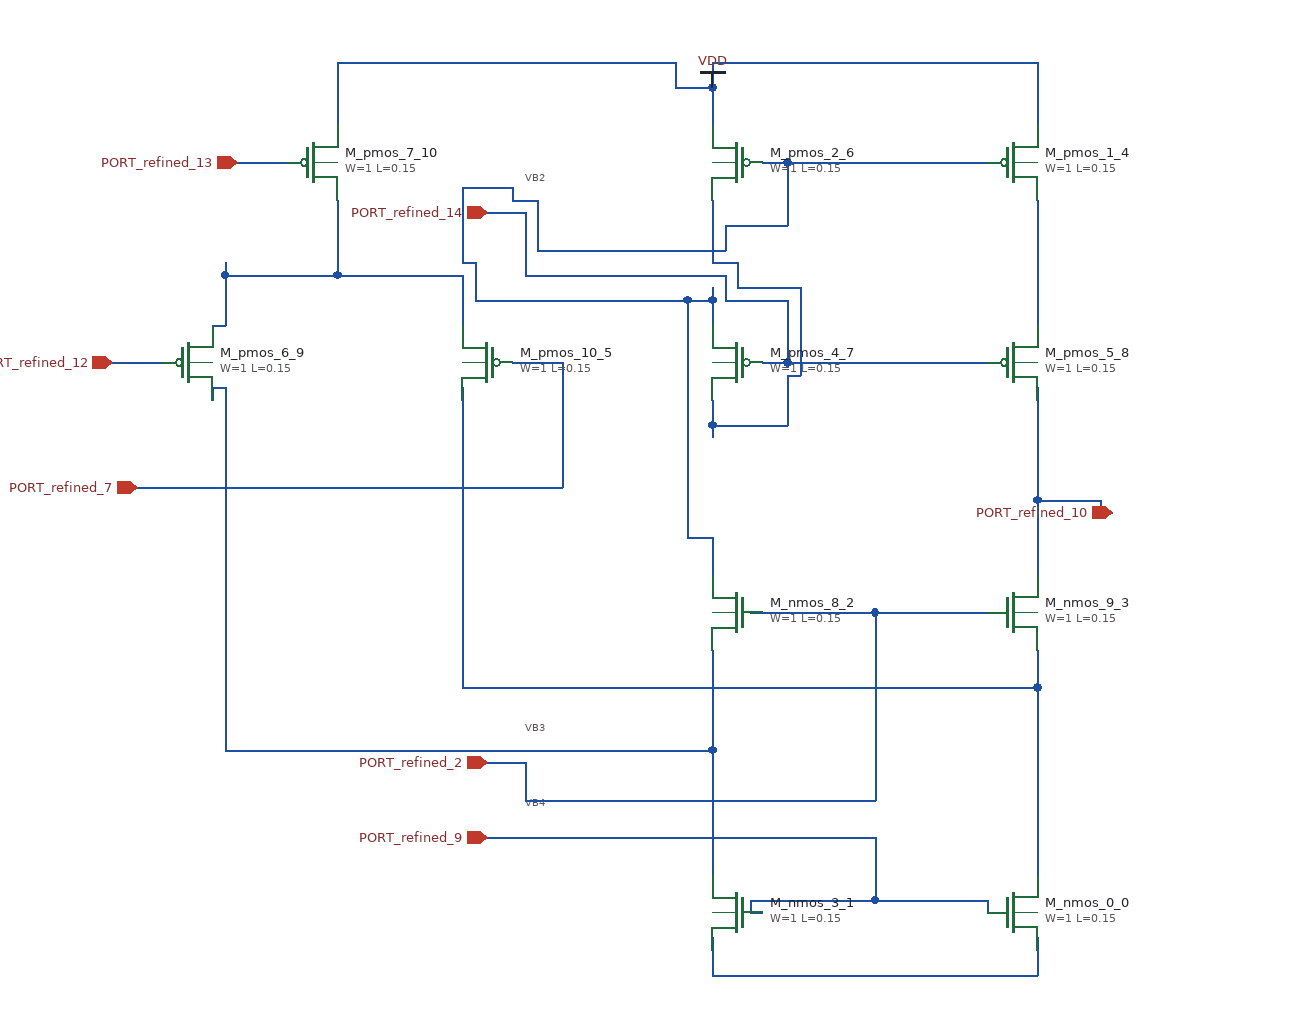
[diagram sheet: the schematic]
v {xschem version=3.4.8 file_version=1.2}
G {}
K {}
V {}
S {}
E {}
C {sky130_fd_pr/nfet3_01v8.sym} 780 720 0 0 {name="M_nmos_0_0"
W=1
L=0.15
body=GND
nf=1
mult=1
ad="expr('int((@nf + 1)/2) * @W / @nf * 0.29')"
pd="expr('2*int((@nf + 1)/2) * (@W / @nf + 0.29)')"
as="expr('int((@nf + 2)/2) * @W / @nf * 0.29')"
ps="expr('2*int((@nf + 2)/2) * (@W / @nf + 0.29)')"
nrd="expr('0.29 / @W ')" nrs="expr('0.29 / @W ')"
sa=0 sb=0 sd=0
model=nfet_01v8
spiceprefix=X
}
C {sky130_fd_pr/nfet3_01v8.sym} 560 720 0 1 {name="M_nmos_3_1"
W=1
L=0.15
body=GND
nf=1
mult=1
ad="expr('int((@nf + 1)/2) * @W / @nf * 0.29')"
pd="expr('2*int((@nf + 1)/2) * (@W / @nf + 0.29)')"
as="expr('int((@nf + 2)/2) * @W / @nf * 0.29')"
ps="expr('2*int((@nf + 2)/2) * (@W / @nf + 0.29)')"
nrd="expr('0.29 / @W ')" nrs="expr('0.29 / @W ')"
sa=0 sb=0 sd=0
model=nfet_01v8
spiceprefix=X
}
C {sky130_fd_pr/nfet3_01v8.sym} 560 480 0 1 {name="M_nmos_8_2"
W=1
L=0.15
body=GND
nf=1
mult=1
ad="expr('int((@nf + 1)/2) * @W / @nf * 0.29')"
pd="expr('2*int((@nf + 1)/2) * (@W / @nf + 0.29)')"
as="expr('int((@nf + 2)/2) * @W / @nf * 0.29')"
ps="expr('2*int((@nf + 2)/2) * (@W / @nf + 0.29)')"
nrd="expr('0.29 / @W ')" nrs="expr('0.29 / @W ')"
sa=0 sb=0 sd=0
model=nfet_01v8
spiceprefix=X
}
C {sky130_fd_pr/nfet3_01v8.sym} 780 480 0 0 {name="M_nmos_9_3"
W=1
L=0.15
body=GND
nf=1
mult=1
ad="expr('int((@nf + 1)/2) * @W / @nf * 0.29')"
pd="expr('2*int((@nf + 1)/2) * (@W / @nf + 0.29)')"
as="expr('int((@nf + 2)/2) * @W / @nf * 0.29')"
ps="expr('2*int((@nf + 2)/2) * (@W / @nf + 0.29)')"
nrd="expr('0.29 / @W ')" nrs="expr('0.29 / @W ')"
sa=0 sb=0 sd=0
model=nfet_01v8
spiceprefix=X
}
C {sky130_fd_pr/pfet3_01v8.sym} 780 120 0 0 {name="M_pmos_1_4"
W=1
L=0.15
body=VDD
nf=1
mult=1
ad="expr('int((@nf + 1)/2) * @W / @nf * 0.29')"
pd="expr('2*int((@nf + 1)/2) * (@W / @nf + 0.29)')"
as="expr('int((@nf + 2)/2) * @W / @nf * 0.29')"
ps="expr('2*int((@nf + 2)/2) * (@W / @nf + 0.29)')"
nrd="expr('0.29 / @W ')" nrs="expr('0.29 / @W ')"
sa=0 sb=0 sd=0
model=pfet_01v8
spiceprefix=X
}
C {sky130_fd_pr/pfet3_01v8.sym} 360 280 0 1 {name="M_pmos_10_5"
W=1
L=0.15
body=VDD
nf=1
mult=1
ad="expr('int((@nf + 1)/2) * @W / @nf * 0.29')"
pd="expr('2*int((@nf + 1)/2) * (@W / @nf + 0.29)')"
as="expr('int((@nf + 2)/2) * @W / @nf * 0.29')"
ps="expr('2*int((@nf + 2)/2) * (@W / @nf + 0.29)')"
nrd="expr('0.29 / @W ')" nrs="expr('0.29 / @W ')"
sa=0 sb=0 sd=0
model=pfet_01v8
spiceprefix=X
}
C {sky130_fd_pr/pfet3_01v8.sym} 560 120 0 1 {name="M_pmos_2_6"
W=1
L=0.15
body=VDD
nf=1
mult=1
ad="expr('int((@nf + 1)/2) * @W / @nf * 0.29')"
pd="expr('2*int((@nf + 1)/2) * (@W / @nf + 0.29)')"
as="expr('int((@nf + 2)/2) * @W / @nf * 0.29')"
ps="expr('2*int((@nf + 2)/2) * (@W / @nf + 0.29)')"
nrd="expr('0.29 / @W ')" nrs="expr('0.29 / @W ')"
sa=0 sb=0 sd=0
model=pfet_01v8
spiceprefix=X
}
C {sky130_fd_pr/pfet3_01v8.sym} 560 280 2 0 {name="M_pmos_4_7"
W=1
L=0.15
body=VDD
nf=1
mult=1
ad="expr('int((@nf + 1)/2) * @W / @nf * 0.29')"
pd="expr('2*int((@nf + 1)/2) * (@W / @nf + 0.29)')"
as="expr('int((@nf + 2)/2) * @W / @nf * 0.29')"
ps="expr('2*int((@nf + 2)/2) * (@W / @nf + 0.29)')"
nrd="expr('0.29 / @W ')" nrs="expr('0.29 / @W ')"
sa=0 sb=0 sd=0
model=pfet_01v8
spiceprefix=X
}
C {sky130_fd_pr/pfet3_01v8.sym} 780 280 0 0 {name="M_pmos_5_8"
W=1
L=0.15
body=VDD
nf=1
mult=1
ad="expr('int((@nf + 1)/2) * @W / @nf * 0.29')"
pd="expr('2*int((@nf + 1)/2) * (@W / @nf + 0.29)')"
as="expr('int((@nf + 2)/2) * @W / @nf * 0.29')"
ps="expr('2*int((@nf + 2)/2) * (@W / @nf + 0.29)')"
nrd="expr('0.29 / @W ')" nrs="expr('0.29 / @W ')"
sa=0 sb=0 sd=0
model=pfet_01v8
spiceprefix=X
}
C {sky130_fd_pr/pfet3_01v8.sym} 120 280 0 0 {name="M_pmos_6_9"
W=1
L=0.15
body=VDD
nf=1
mult=1
ad="expr('int((@nf + 1)/2) * @W / @nf * 0.29')"
pd="expr('2*int((@nf + 1)/2) * (@W / @nf + 0.29)')"
as="expr('int((@nf + 2)/2) * @W / @nf * 0.29')"
ps="expr('2*int((@nf + 2)/2) * (@W / @nf + 0.29)')"
nrd="expr('0.29 / @W ')" nrs="expr('0.29 / @W ')"
sa=0 sb=0 sd=0
model=pfet_01v8
spiceprefix=X
}
C {sky130_fd_pr/pfet3_01v8.sym} 220 120 0 0 {name="M_pmos_7_10"
W=1
L=0.15
body=VDD
nf=1
mult=1
ad="expr('int((@nf + 1)/2) * @W / @nf * 0.29')"
pd="expr('2*int((@nf + 1)/2) * (@W / @nf + 0.29)')"
as="expr('int((@nf + 2)/2) * @W / @nf * 0.29')"
ps="expr('2*int((@nf + 2)/2) * (@W / @nf + 0.29)')"
nrd="expr('0.29 / @W ')" nrs="expr('0.29 / @W ')"
sa=0 sb=0 sd=0
model=pfet_01v8
spiceprefix=X
}
C {devices/ipin.sym} 60 280 0 0 {name="p_port_12_11" lab="PORT_refined_12"}
C {devices/ipin.sym} 860 400 0 0 {name="p_port_13_12" lab="PORT_refined_10"}
C {devices/ipin.sym} 160 120 0 0 {name="p_port_14_13" lab="PORT_refined_13"}
C {devices/ipin.sym} 80 380 0 0 {name="p_port_15_14" lab="PORT_refined_7"}
C {devices/ipin.sym} 360 160 0 0 {name="p_port_20_15" lab="PORT_refined_14"}
T {VB2} 390 120 0 0 0.25 0.25 {}
C {devices/ipin.sym} 360 600 0 0 {name="p_port_21_16" lab="PORT_refined_2"}
T {VB3} 390 560 0 0 0.25 0.25 {}
C {devices/ipin.sym} 360 660 0 0 {name="p_port_22_17" lab="PORT_refined_9"}
T {VB4} 390 620 0 0 0.25 0.25 {}
C {devices/vdd.sym} 540 60 0 0 {name="l_vdd_11_18" lab="VDD"}
N 340 540 800 540 {}
N 340 540 340 310 {}
N 340 310 340 300 {}
N 800 690 800 540 {}
N 800 540 800 510 {}
N 540 770 800 770 {}
N 540 770 540 750 {}
N 540 750 540 740 {}
N 800 770 800 750 {}
N 800 750 800 740 {}
N 850 400 860 400 {}
N 800 390 850 390 {}
N 800 460 800 450 {}
N 800 450 800 390 {}
N 800 390 800 310 {}
N 800 310 800 300 {}
N 850 400 850 390 {}
N 150 590 540 590 {}
N 140 300 150 300 {}
N 140 310 140 300 {}
N 150 590 150 300 {}
N 540 690 540 590 {}
N 540 590 540 510 {}
N 60 280 100 280 {}
N 100 280 110 280 {}
N 160 120 200 120 {}
N 580 280 600 280 {}
N 600 280 760 280 {}
N 550 230 600 230 {}
N 390 210 550 210 {}
N 360 160 390 160 {}
N 390 210 390 160 {}
N 550 230 550 210 {}
N 600 280 600 230 {}
N 390 630 670 630 {}
N 360 600 390 600 {}
N 570 480 580 480 {}
N 580 480 670 480 {}
N 670 480 760 480 {}
N 390 630 390 600 {}
N 670 630 670 480 {}
N 510 60 540 60 {}
N 240 40 510 40 {}
N 540 40 800 40 {}
N 240 90 240 40 {}
N 510 60 510 40 {}
N 540 90 540 60 {}
N 540 60 540 40 {}
N 800 90 800 40 {}
N 800 250 800 150 {}
N 520 420 540 420 {}
N 350 230 520 230 {}
N 520 230 540 230 {}
N 340 200 350 200 {}
N 400 190 550 190 {}
N 550 170 600 170 {}
N 380 150 400 150 {}
N 340 140 380 140 {}
N 580 120 600 120 {}
N 600 120 760 120 {}
N 340 200 340 140 {}
N 350 230 350 200 {}
N 380 150 380 140 {}
N 400 190 400 150 {}
N 520 420 520 230 {}
N 540 450 540 420 {}
N 540 250 540 230 {}
N 540 230 540 220 {}
N 550 190 550 170 {}
N 600 170 600 120 {}
N 140 250 150 250 {}
N 150 210 240 210 {}
N 240 210 340 210 {}
N 150 250 150 210 {}
N 150 210 150 200 {}
N 240 210 240 150 {}
N 340 250 340 210 {}
N 80 380 420 380 {}
N 380 280 420 280 {}
N 420 380 420 280 {}
N 540 330 600 330 {}
N 600 290 610 290 {}
N 560 220 610 220 {}
N 540 200 560 200 {}
N 540 340 540 330 {}
N 540 330 540 310 {}
N 540 200 540 150 {}
N 560 220 560 200 {}
N 600 330 600 290 {}
N 610 290 610 220 {}
N 570 720 580 720 {}
N 570 710 670 710 {}
N 670 710 760 710 {}
N 360 660 670 660 {}
N 570 720 570 710 {}
N 670 710 670 660 {}
N 760 720 760 710 {}
